VERSION 5.7 ;
BUSBITCHARS "[]" ;
DIVIDERCHAR "/" ;
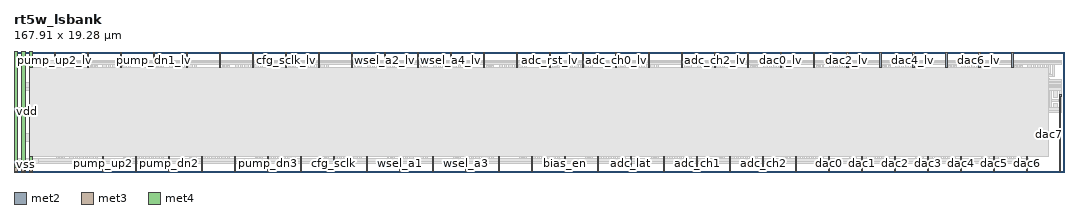
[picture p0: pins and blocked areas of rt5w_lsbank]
MACRO rt5w_lsbank
  CLASS BLOCK ;
  FOREIGN rt5w_lsbank ;
  ORIGIN 3.900 1.500 ;
  SIZE 167.910 BY 19.280 ;
  SYMMETRY X Y ;
  PIN adc_ch0
    DIRECTION INOUT ;
    USE SIGNAL ;
    PORT
      LAYER met2 ;
        RECT 99.945 -1.400 100.145 1.000 ;
    END
  END adc_ch0
  PIN adc_ch0_lv
    DIRECTION INOUT ;
    USE SIGNAL ;
    PORT
      LAYER met2 ;
        RECT 92.310 15.280 92.510 17.680 ;
    END
  END adc_ch0_lv
  PIN adc_ch1
    DIRECTION INOUT ;
    USE SIGNAL ;
    PORT
      LAYER met2 ;
        RECT 105.225 -1.400 105.425 1.000 ;
    END
  END adc_ch1
  PIN adc_ch1_lv
    DIRECTION INOUT ;
    USE SIGNAL ;
    PORT
      LAYER met2 ;
        RECT 97.590 15.280 97.790 17.680 ;
    END
  END adc_ch1_lv
  PIN adc_ch2
    DIRECTION INOUT ;
    USE SIGNAL ;
    PORT
      LAYER met2 ;
        RECT 115.785 -1.400 115.985 1.000 ;
    END
  END adc_ch2
  PIN adc_ch2_lv
    DIRECTION INOUT ;
    USE SIGNAL ;
    PORT
      LAYER met2 ;
        RECT 108.150 15.280 108.350 17.680 ;
    END
  END adc_ch2_lv
  PIN adc_ch3
    DIRECTION INOUT ;
    USE SIGNAL ;
    PORT
      LAYER met2 ;
        RECT 121.065 -1.400 121.265 1.000 ;
    END
  END adc_ch3
  PIN adc_ch3_lv
    DIRECTION INOUT ;
    USE SIGNAL ;
    PORT
      LAYER met2 ;
        RECT 113.430 15.280 113.630 17.680 ;
    END
  END adc_ch3_lv
  PIN adc_lat
    DIRECTION INOUT ;
    USE SIGNAL ;
    PORT
      LAYER met2 ;
        RECT 94.665 -1.400 94.865 1.000 ;
    END
  END adc_lat
  PIN adc_lat_lv
    DIRECTION INOUT ;
    USE SIGNAL ;
    PORT
      LAYER met2 ;
        RECT 87.030 15.280 87.230 17.680 ;
    END
  END adc_lat_lv
  PIN adc_rst
    DIRECTION INOUT ;
    USE SIGNAL ;
    PORT
      LAYER met2 ;
        RECT 89.385 -1.400 89.585 1.000 ;
    END
  END adc_rst
  PIN adc_rst_lv
    DIRECTION INOUT ;
    USE SIGNAL ;
    PORT
      LAYER met2 ;
        RECT 81.750 15.280 81.950 17.680 ;
    END
  END adc_rst_lv
  PIN bias_en
    DIRECTION INOUT ;
    USE SIGNAL ;
    PORT
      LAYER met2 ;
        RECT 84.105 -1.400 84.305 1.000 ;
    END
  END bias_en
  PIN bias_en_lv
    DIRECTION INOUT ;
    USE SIGNAL ;
    PORT
      LAYER met2 ;
        RECT 76.470 15.280 76.670 17.680 ;
    END
  END bias_en_lv
  PIN cfg_sclk
    DIRECTION INOUT ;
    USE SIGNAL ;
    PORT
      LAYER met2 ;
        RECT 47.145 -1.400 47.345 1.000 ;
    END
  END cfg_sclk
  PIN cfg_sclk_lv
    DIRECTION INOUT ;
    USE SIGNAL ;
    PORT
      LAYER met2 ;
        RECT 39.510 15.280 39.710 17.680 ;
    END
  END cfg_sclk_lv
  PIN cfg_sdat
    DIRECTION INOUT ;
    USE SIGNAL ;
    PORT
      LAYER met2 ;
        RECT 41.865 -1.400 42.065 1.000 ;
    END
  END cfg_sdat
  PIN cfg_sdat_lv
    DIRECTION INOUT ;
    USE SIGNAL ;
    PORT
      LAYER met2 ;
        RECT 34.230 15.280 34.430 17.680 ;
    END
  END cfg_sdat_lv
  PIN dac0
    DIRECTION INOUT ;
    USE SIGNAL ;
    PORT
      LAYER met2 ;
        RECT 126.345 -1.400 126.545 1.000 ;
    END
  END dac0
  PIN dac0_lv
    DIRECTION INOUT ;
    USE SIGNAL ;
    PORT
      LAYER met2 ;
        RECT 118.710 15.280 118.910 17.680 ;
    END
  END dac0_lv
  PIN dac1
    DIRECTION INOUT ;
    USE SIGNAL ;
    PORT
      LAYER met2 ;
        RECT 131.625 -1.400 131.825 1.000 ;
    END
  END dac1
  PIN dac1_lv
    DIRECTION INOUT ;
    USE SIGNAL ;
    PORT
      LAYER met2 ;
        RECT 123.990 15.280 124.190 17.680 ;
    END
  END dac1_lv
  PIN dac2
    DIRECTION INOUT ;
    USE SIGNAL ;
    PORT
      LAYER met2 ;
        RECT 136.905 -1.400 137.105 1.000 ;
    END
  END dac2
  PIN dac2_lv
    DIRECTION INOUT ;
    USE SIGNAL ;
    PORT
      LAYER met2 ;
        RECT 129.270 15.280 129.470 17.680 ;
    END
  END dac2_lv
  PIN dac3
    DIRECTION INOUT ;
    USE SIGNAL ;
    PORT
      LAYER met2 ;
        RECT 142.185 -1.400 142.385 1.000 ;
    END
  END dac3
  PIN dac3_lv
    DIRECTION INOUT ;
    USE SIGNAL ;
    PORT
      LAYER met2 ;
        RECT 134.550 15.280 134.750 17.680 ;
    END
  END dac3_lv
  PIN dac4
    DIRECTION INOUT ;
    USE SIGNAL ;
    PORT
      LAYER met2 ;
        RECT 147.465 -1.400 147.665 1.000 ;
    END
  END dac4
  PIN dac4_lv
    DIRECTION INOUT ;
    USE SIGNAL ;
    PORT
      LAYER met2 ;
        RECT 139.830 15.280 140.030 17.680 ;
    END
  END dac4_lv
  PIN dac5
    DIRECTION INOUT ;
    USE SIGNAL ;
    PORT
      LAYER met2 ;
        RECT 152.745 -1.400 152.945 1.000 ;
    END
  END dac5
  PIN dac5_lv
    DIRECTION INOUT ;
    USE SIGNAL ;
    PORT
      LAYER met2 ;
        RECT 145.110 15.280 145.310 17.680 ;
    END
  END dac5_lv
  PIN dac6
    DIRECTION INOUT ;
    USE SIGNAL ;
    PORT
      LAYER met2 ;
        RECT 158.025 -1.400 158.225 1.000 ;
    END
  END dac6
  PIN dac6_lv
    DIRECTION INOUT ;
    USE SIGNAL ;
    PORT
      LAYER met2 ;
        RECT 150.390 15.280 150.590 17.680 ;
    END
  END dac6_lv
  PIN dac7
    DIRECTION INOUT ;
    USE SIGNAL ;
    PORT
      LAYER met2 ;
        RECT 163.275 10.520 163.535 10.840 ;
        RECT 163.305 -1.400 163.505 10.520 ;
    END
  END dac7
  PIN dac7_lv
    DIRECTION INOUT ;
    USE SIGNAL ;
    PORT
      LAYER met2 ;
        RECT 155.670 15.280 155.870 17.680 ;
    END
  END dac7_lv
  PIN pump_dn1
    DIRECTION INOUT ;
    USE SIGNAL ;
    PORT
      LAYER met2 ;
        RECT 26.025 -1.400 26.225 1.000 ;
    END
  END pump_dn1
  PIN pump_dn1_lv
    DIRECTION INOUT ;
    USE SIGNAL ;
    PORT
      LAYER met2 ;
        RECT 18.390 15.280 18.590 17.680 ;
    END
  END pump_dn1_lv
  PIN pump_dn2
    DIRECTION INOUT ;
    USE SIGNAL ;
    PORT
      LAYER met2 ;
        RECT 20.745 -1.400 20.945 1.000 ;
    END
  END pump_dn2
  PIN pump_dn2_lv
    DIRECTION INOUT ;
    USE SIGNAL ;
    PORT
      LAYER met2 ;
        RECT 13.110 15.280 13.310 17.680 ;
    END
  END pump_dn2_lv
  PIN pump_dn3
    DIRECTION INOUT ;
    USE SIGNAL ;
    PORT
      LAYER met2 ;
        RECT 36.585 -1.400 36.785 1.000 ;
    END
  END pump_dn3
  PIN pump_dn3_lv
    DIRECTION INOUT ;
    USE SIGNAL ;
    PORT
      LAYER met2 ;
        RECT 28.950 15.280 29.150 17.680 ;
    END
  END pump_dn3_lv
  PIN pump_up1
    DIRECTION INOUT ;
    USE SIGNAL ;
    PORT
      LAYER met2 ;
        RECT 15.465 -1.400 15.665 1.000 ;
    END
  END pump_up1
  PIN pump_up1_lv
    DIRECTION INOUT ;
    USE SIGNAL ;
    PORT
      LAYER met2 ;
        RECT 7.830 15.280 8.030 17.680 ;
    END
  END pump_up1_lv
  PIN pump_up2
    DIRECTION INOUT ;
    USE SIGNAL ;
    PORT
      LAYER met2 ;
        RECT 10.185 -1.400 10.385 1.000 ;
    END
  END pump_up2
  PIN pump_up2_lv
    DIRECTION INOUT ;
    USE SIGNAL ;
    PORT
      LAYER met2 ;
        RECT 2.550 15.280 2.750 17.680 ;
    END
  END pump_up2_lv
  PIN pump_up3
    DIRECTION INOUT ;
    USE SIGNAL ;
    PORT
      LAYER met2 ;
        RECT 31.305 -1.400 31.505 1.000 ;
    END
  END pump_up3
  PIN pump_up3_lv
    DIRECTION INOUT ;
    USE SIGNAL ;
    PORT
      LAYER met2 ;
        RECT 23.670 15.280 23.870 17.680 ;
    END
  END pump_up3_lv
  PIN vb_probe_en
    DIRECTION INOUT ;
    USE SIGNAL ;
    PORT
      LAYER met2 ;
        RECT 110.505 -1.400 110.705 1.000 ;
    END
  END vb_probe_en
  PIN vb_probe_en_lv
    DIRECTION INOUT ;
    USE SIGNAL ;
    PORT
      LAYER met2 ;
        RECT 102.870 15.280 103.070 17.680 ;
    END
  END vb_probe_en_lv
  PIN vdd
    DIRECTION INOUT ;
    USE SIGNAL ;
    PORT
      LAYER met3 ;
        RECT -2.650 -1.350 -2.150 -0.850 ;
      LAYER met4 ;
        RECT -2.700 -1.500 -2.100 17.780 ;
    END
  END vdd
  PIN vddl
    DIRECTION INOUT ;
    USE SIGNAL ;
    PORT
      LAYER met3 ;
        RECT -1.450 -1.350 -0.950 -0.850 ;
      LAYER met4 ;
        RECT -1.500 -1.500 -0.900 1.000 ;
        RECT -1.500 1.000 -1.400 15.280 ;
        RECT -1.500 15.280 -0.900 17.780 ;
    END
  END vddl
  PIN vss
    DIRECTION INOUT ;
    USE SIGNAL ;
    PORT
      LAYER met3 ;
        RECT -3.850 -1.350 -3.350 -0.850 ;
      LAYER met4 ;
        RECT -3.900 -1.500 -3.300 17.780 ;
    END
  END vss
  PIN wsel_a0
    DIRECTION INOUT ;
    USE SIGNAL ;
    PORT
      LAYER met2 ;
        RECT 52.425 -1.400 52.625 1.000 ;
    END
  END wsel_a0
  PIN wsel_a0_lv
    DIRECTION INOUT ;
    USE SIGNAL ;
    PORT
      LAYER met2 ;
        RECT 44.790 15.280 44.990 17.680 ;
    END
  END wsel_a0_lv
  PIN wsel_a1
    DIRECTION INOUT ;
    USE SIGNAL ;
    PORT
      LAYER met2 ;
        RECT 57.705 -1.400 57.905 1.000 ;
    END
  END wsel_a1
  PIN wsel_a1_lv
    DIRECTION INOUT ;
    USE SIGNAL ;
    PORT
      LAYER met2 ;
        RECT 50.070 15.280 50.270 17.680 ;
    END
  END wsel_a1_lv
  PIN wsel_a2
    DIRECTION INOUT ;
    USE SIGNAL ;
    PORT
      LAYER met2 ;
        RECT 62.985 -1.400 63.185 1.000 ;
    END
  END wsel_a2
  PIN wsel_a2_lv
    DIRECTION INOUT ;
    USE SIGNAL ;
    PORT
      LAYER met2 ;
        RECT 55.350 15.280 55.550 17.680 ;
    END
  END wsel_a2_lv
  PIN wsel_a3
    DIRECTION INOUT ;
    USE SIGNAL ;
    PORT
      LAYER met2 ;
        RECT 68.265 -1.400 68.465 1.000 ;
    END
  END wsel_a3
  PIN wsel_a3_lv
    DIRECTION INOUT ;
    USE SIGNAL ;
    PORT
      LAYER met2 ;
        RECT 60.630 15.280 60.830 17.680 ;
    END
  END wsel_a3_lv
  PIN wsel_a4
    DIRECTION INOUT ;
    USE SIGNAL ;
    PORT
      LAYER met2 ;
        RECT 73.545 -1.400 73.745 1.000 ;
    END
  END wsel_a4
  PIN wsel_a4_lv
    DIRECTION INOUT ;
    USE SIGNAL ;
    PORT
      LAYER met2 ;
        RECT 65.910 15.280 66.110 17.680 ;
    END
  END wsel_a4_lv
  PIN wsel_e
    DIRECTION INOUT ;
    USE SIGNAL ;
    PORT
      LAYER met2 ;
        RECT 78.825 -1.400 79.025 1.000 ;
    END
  END wsel_e
  PIN wsel_e_lv
    DIRECTION INOUT ;
    USE SIGNAL ;
    PORT
      LAYER met2 ;
        RECT 71.190 15.280 71.390 17.680 ;
    END
  END wsel_e_lv
  OBS
    LAYER li1 ;
      RECT 0.000 -0.085 158.400 0.085 ;
      RECT 78.970 0.255 82.090 0.425 ;
      RECT -1.400 1.000 161.510 13.805 ;
      RECT -1.400 13.805 162.200 14.135 ;
      RECT -1.400 14.135 161.290 15.280 ;
      RECT 5.280 16.195 163.680 16.365 ;
      RECT 122.120 0.595 122.450 1.000 ;
      RECT 121.210 0.255 124.330 0.425 ;
      RECT 162.330 8.535 162.920 9.445 ;
      RECT 163.330 9.555 163.570 10.225 ;
      RECT 122.770 0.425 123.360 1.000 ;
      RECT 123.680 0.595 124.010 1.000 ;
      RECT 124.330 0.255 124.920 1.000 ;
      RECT 163.240 8.655 163.570 9.555 ;
      RECT 125.240 0.515 125.570 1.000 ;
      RECT 129.695 0.735 129.985 1.000 ;
      RECT 130.155 0.565 130.425 1.000 ;
      RECT 129.815 0.335 130.765 0.565 ;
      RECT 130.595 0.735 130.905 1.000 ;
      RECT 131.770 0.425 132.360 1.000 ;
      RECT 132.680 0.595 133.010 1.000 ;
      RECT 133.330 0.425 133.920 1.000 ;
      RECT 134.240 0.595 134.570 1.000 ;
      RECT 134.890 0.255 135.480 1.000 ;
      RECT 131.770 0.255 134.890 0.425 ;
      RECT 135.800 0.515 136.130 1.000 ;
      RECT 140.255 0.735 140.545 1.000 ;
      RECT 140.715 0.565 140.985 1.000 ;
      RECT 140.375 0.335 141.325 0.565 ;
      RECT 141.155 0.735 141.465 1.000 ;
      RECT 142.330 0.425 142.920 1.000 ;
      RECT 143.240 0.595 143.570 1.000 ;
      RECT 143.890 0.425 144.480 1.000 ;
      RECT 144.800 0.595 145.130 1.000 ;
      RECT 145.450 0.255 146.040 1.000 ;
      RECT 142.330 0.255 145.450 0.425 ;
      RECT 146.360 0.515 146.690 1.000 ;
      RECT 150.815 0.735 151.105 1.000 ;
      RECT 151.275 0.565 151.545 1.000 ;
      RECT 150.935 0.335 151.885 0.565 ;
      RECT 151.715 0.735 152.025 1.000 ;
      RECT 152.890 0.425 153.480 1.000 ;
      RECT 153.800 0.595 154.130 1.000 ;
      RECT 154.450 0.425 155.040 1.000 ;
      RECT 155.360 0.595 155.690 1.000 ;
      RECT 156.010 0.255 156.600 1.000 ;
      RECT 152.890 0.255 156.010 0.425 ;
      RECT 124.415 15.280 124.705 15.545 ;
      RECT 125.315 15.280 125.625 15.545 ;
      RECT 134.975 15.280 135.265 15.545 ;
      RECT 135.875 15.280 136.185 15.545 ;
      RECT 145.535 15.280 145.825 15.545 ;
      RECT 146.435 15.280 146.745 15.545 ;
      RECT 156.095 15.280 156.385 15.545 ;
      RECT 156.995 15.280 157.305 15.545 ;
      RECT 127.400 15.280 127.730 15.685 ;
      RECT 128.960 15.280 129.290 15.685 ;
      RECT 137.960 15.280 138.290 15.685 ;
      RECT 139.520 15.280 139.850 15.685 ;
      RECT 148.520 15.280 148.850 15.685 ;
      RECT 150.080 15.280 150.410 15.685 ;
      RECT 159.080 15.280 159.410 15.685 ;
      RECT 160.640 15.280 160.970 15.685 ;
      RECT 130.520 15.280 130.850 15.765 ;
      RECT 141.080 15.280 141.410 15.765 ;
      RECT 151.640 15.280 151.970 15.765 ;
      RECT 161.510 8.055 163.680 8.225 ;
      RECT 161.965 9.725 163.160 10.055 ;
      RECT 156.920 0.515 157.250 1.000 ;
      RECT 162.200 13.805 162.530 15.765 ;
      RECT 161.635 8.655 161.965 11.875 ;
      RECT 161.510 12.575 161.715 13.485 ;
      RECT 161.510 12.125 163.680 12.295 ;
      RECT 126.490 15.280 127.080 15.855 ;
      RECT 128.050 15.280 128.640 15.855 ;
      RECT 137.050 15.280 137.640 15.855 ;
      RECT 138.610 15.280 139.200 15.855 ;
      RECT 147.610 15.280 148.200 15.855 ;
      RECT 149.170 15.280 149.760 15.855 ;
      RECT 158.170 15.280 158.760 15.855 ;
      RECT 159.730 15.280 160.320 15.855 ;
      RECT 124.535 15.715 125.485 15.945 ;
      RECT 124.875 15.280 125.145 15.715 ;
      RECT 135.095 15.715 136.045 15.945 ;
      RECT 135.435 15.280 135.705 15.715 ;
      RECT 145.655 15.715 146.605 15.945 ;
      RECT 145.995 15.280 146.265 15.715 ;
      RECT 156.215 15.715 157.165 15.945 ;
      RECT 156.555 15.280 156.825 15.715 ;
      RECT 126.490 15.855 129.610 16.025 ;
      RECT 129.610 15.280 130.200 16.025 ;
      RECT 137.050 15.855 140.170 16.025 ;
      RECT 140.170 15.280 140.760 16.025 ;
      RECT 147.610 15.855 150.730 16.025 ;
      RECT 150.730 15.280 151.320 16.025 ;
      RECT 158.170 15.855 161.880 16.025 ;
      RECT 161.290 14.135 161.510 15.855 ;
      RECT 161.510 14.305 161.880 15.855 ;
      RECT 162.330 10.335 162.920 11.875 ;
      RECT 163.240 10.225 163.570 11.875 ;
      RECT 81.440 0.595 81.770 1.000 ;
      RECT 83.000 0.515 83.330 1.000 ;
      RECT 87.455 0.735 87.745 1.000 ;
      RECT 87.915 0.565 88.185 1.000 ;
      RECT 85.160 15.280 85.490 15.685 ;
      RECT 86.720 15.280 87.050 15.685 ;
      RECT 95.720 15.280 96.050 15.685 ;
      RECT 97.280 15.280 97.610 15.685 ;
      RECT 106.280 15.280 106.610 15.685 ;
      RECT 107.840 15.280 108.170 15.685 ;
      RECT 116.840 15.280 117.170 15.685 ;
      RECT 118.400 15.280 118.730 15.685 ;
      RECT 87.575 0.335 88.525 0.565 ;
      RECT 88.355 0.735 88.665 1.000 ;
      RECT 89.530 0.425 90.120 1.000 ;
      RECT 90.440 0.595 90.770 1.000 ;
      RECT 91.090 0.425 91.680 1.000 ;
      RECT 92.000 0.595 92.330 1.000 ;
      RECT 92.650 0.255 93.240 1.000 ;
      RECT 89.530 0.255 92.650 0.425 ;
      RECT 88.280 15.280 88.610 15.765 ;
      RECT 98.840 15.280 99.170 15.765 ;
      RECT 109.400 15.280 109.730 15.765 ;
      RECT 119.960 15.280 120.290 15.765 ;
      RECT 93.560 0.515 93.890 1.000 ;
      RECT 98.015 0.735 98.305 1.000 ;
      RECT 98.475 0.565 98.745 1.000 ;
      RECT 98.135 0.335 99.085 0.565 ;
      RECT 98.915 0.735 99.225 1.000 ;
      RECT 100.090 0.425 100.680 1.000 ;
      RECT 101.000 0.595 101.330 1.000 ;
      RECT 101.650 0.425 102.240 1.000 ;
      RECT 102.560 0.595 102.890 1.000 ;
      RECT 103.210 0.255 103.800 1.000 ;
      RECT 84.250 15.280 84.840 15.855 ;
      RECT 85.810 15.280 86.400 15.855 ;
      RECT 94.810 15.280 95.400 15.855 ;
      RECT 96.370 15.280 96.960 15.855 ;
      RECT 105.370 15.280 105.960 15.855 ;
      RECT 106.930 15.280 107.520 15.855 ;
      RECT 115.930 15.280 116.520 15.855 ;
      RECT 117.490 15.280 118.080 15.855 ;
      RECT 100.090 0.255 103.210 0.425 ;
      RECT 104.120 0.515 104.450 1.000 ;
      RECT 108.575 0.735 108.865 1.000 ;
      RECT 109.035 0.565 109.305 1.000 ;
      RECT 108.695 0.335 109.645 0.565 ;
      RECT 109.475 0.735 109.785 1.000 ;
      RECT 110.650 0.425 111.240 1.000 ;
      RECT 111.560 0.595 111.890 1.000 ;
      RECT 82.295 15.715 83.245 15.945 ;
      RECT 82.635 15.280 82.905 15.715 ;
      RECT 92.855 15.715 93.805 15.945 ;
      RECT 93.195 15.280 93.465 15.715 ;
      RECT 103.415 15.715 104.365 15.945 ;
      RECT 103.755 15.280 104.025 15.715 ;
      RECT 113.975 15.715 114.925 15.945 ;
      RECT 114.315 15.280 114.585 15.715 ;
      RECT 112.210 0.425 112.800 1.000 ;
      RECT 113.120 0.595 113.450 1.000 ;
      RECT 113.770 0.255 114.360 1.000 ;
      RECT 110.650 0.255 113.770 0.425 ;
      RECT 114.680 0.515 115.010 1.000 ;
      RECT 119.135 0.735 119.425 1.000 ;
      RECT 119.595 0.565 119.865 1.000 ;
      RECT 82.175 15.280 82.465 15.545 ;
      RECT 84.250 15.855 87.370 16.025 ;
      RECT 87.370 15.280 87.960 16.025 ;
      RECT 94.810 15.855 97.930 16.025 ;
      RECT 97.930 15.280 98.520 16.025 ;
      RECT 105.370 15.855 108.490 16.025 ;
      RECT 108.490 15.280 109.080 16.025 ;
      RECT 115.930 15.855 119.050 16.025 ;
      RECT 119.050 15.280 119.640 16.025 ;
      RECT 83.075 15.280 83.385 15.545 ;
      RECT 92.735 15.280 93.025 15.545 ;
      RECT 93.635 15.280 93.945 15.545 ;
      RECT 103.295 15.280 103.585 15.545 ;
      RECT 104.195 15.280 104.505 15.545 ;
      RECT 113.855 15.280 114.145 15.545 ;
      RECT 114.755 15.280 115.065 15.545 ;
      RECT 119.255 0.335 120.205 0.565 ;
      RECT 120.035 0.735 120.345 1.000 ;
      RECT 121.210 0.425 121.800 1.000 ;
      RECT 82.090 0.255 82.680 1.000 ;
      RECT 39.850 0.255 40.440 1.000 ;
      RECT 77.795 0.735 78.105 1.000 ;
      RECT 78.970 0.425 79.560 1.000 ;
      RECT 79.880 0.595 80.210 1.000 ;
      RECT 80.530 0.425 81.120 1.000 ;
      RECT 42.920 15.280 43.250 15.685 ;
      RECT 44.480 15.280 44.810 15.685 ;
      RECT 53.480 15.280 53.810 15.685 ;
      RECT 55.040 15.280 55.370 15.685 ;
      RECT 64.040 15.280 64.370 15.685 ;
      RECT 65.600 15.280 65.930 15.685 ;
      RECT 74.600 15.280 74.930 15.685 ;
      RECT 76.160 15.280 76.490 15.685 ;
      RECT 46.040 15.280 46.370 15.765 ;
      RECT 56.600 15.280 56.930 15.765 ;
      RECT 67.160 15.280 67.490 15.765 ;
      RECT 77.720 15.280 78.050 15.765 ;
      RECT 72.515 15.280 72.825 15.545 ;
      RECT 42.010 15.280 42.600 15.855 ;
      RECT 43.570 15.280 44.160 15.855 ;
      RECT 52.570 15.280 53.160 15.855 ;
      RECT 54.130 15.280 54.720 15.855 ;
      RECT 63.130 15.280 63.720 15.855 ;
      RECT 64.690 15.280 65.280 15.855 ;
      RECT 73.690 15.280 74.280 15.855 ;
      RECT 75.250 15.280 75.840 15.855 ;
      RECT 40.760 0.515 41.090 1.000 ;
      RECT 45.215 0.735 45.505 1.000 ;
      RECT 45.675 0.565 45.945 1.000 ;
      RECT 45.335 0.335 46.285 0.565 ;
      RECT 46.115 0.735 46.425 1.000 ;
      RECT 47.290 0.425 47.880 1.000 ;
      RECT 48.200 0.595 48.530 1.000 ;
      RECT 48.850 0.425 49.440 1.000 ;
      RECT 49.760 0.595 50.090 1.000 ;
      RECT 50.410 0.255 51.000 1.000 ;
      RECT 47.290 0.255 50.410 0.425 ;
      RECT 51.320 0.515 51.650 1.000 ;
      RECT 55.775 0.735 56.065 1.000 ;
      RECT 56.235 0.565 56.505 1.000 ;
      RECT 55.895 0.335 56.845 0.565 ;
      RECT 40.055 15.715 41.005 15.945 ;
      RECT 40.395 15.280 40.665 15.715 ;
      RECT 50.615 15.715 51.565 15.945 ;
      RECT 50.955 15.280 51.225 15.715 ;
      RECT 61.175 15.715 62.125 15.945 ;
      RECT 61.515 15.280 61.785 15.715 ;
      RECT 71.735 15.715 72.685 15.945 ;
      RECT 72.075 15.280 72.345 15.715 ;
      RECT 56.675 0.735 56.985 1.000 ;
      RECT 57.850 0.425 58.440 1.000 ;
      RECT 58.760 0.595 59.090 1.000 ;
      RECT 59.410 0.425 60.000 1.000 ;
      RECT 60.320 0.595 60.650 1.000 ;
      RECT 60.970 0.255 61.560 1.000 ;
      RECT 57.850 0.255 60.970 0.425 ;
      RECT 61.880 0.515 62.210 1.000 ;
      RECT 66.335 0.735 66.625 1.000 ;
      RECT 66.795 0.565 67.065 1.000 ;
      RECT 66.455 0.335 67.405 0.565 ;
      RECT 67.235 0.735 67.545 1.000 ;
      RECT 68.410 0.425 69.000 1.000 ;
      RECT 69.320 0.595 69.650 1.000 ;
      RECT 69.970 0.425 70.560 1.000 ;
      RECT 70.880 0.595 71.210 1.000 ;
      RECT 42.010 15.855 45.130 16.025 ;
      RECT 45.130 15.280 45.720 16.025 ;
      RECT 52.570 15.855 55.690 16.025 ;
      RECT 55.690 15.280 56.280 16.025 ;
      RECT 63.130 15.855 66.250 16.025 ;
      RECT 66.250 15.280 66.840 16.025 ;
      RECT 73.690 15.855 76.810 16.025 ;
      RECT 76.810 15.280 77.400 16.025 ;
      RECT 71.530 0.255 72.120 1.000 ;
      RECT 68.410 0.255 71.530 0.425 ;
      RECT 72.440 0.515 72.770 1.000 ;
      RECT 76.895 0.735 77.185 1.000 ;
      RECT 77.355 0.565 77.625 1.000 ;
      RECT 77.015 0.335 77.965 0.565 ;
      RECT 39.935 15.280 40.225 15.545 ;
      RECT 40.835 15.280 41.145 15.545 ;
      RECT 50.495 15.280 50.785 15.545 ;
      RECT 51.395 15.280 51.705 15.545 ;
      RECT 61.055 15.280 61.345 15.545 ;
      RECT 61.955 15.280 62.265 15.545 ;
      RECT 71.615 15.280 71.905 15.545 ;
      RECT 6.610 0.425 7.200 1.000 ;
      RECT 7.520 0.595 7.850 1.000 ;
      RECT 13.995 0.565 14.265 1.000 ;
      RECT 13.655 0.335 14.605 0.565 ;
      RECT 14.435 0.735 14.745 1.000 ;
      RECT 15.610 0.425 16.200 1.000 ;
      RECT 16.520 0.595 16.850 1.000 ;
      RECT 17.170 0.425 17.760 1.000 ;
      RECT 18.080 0.595 18.410 1.000 ;
      RECT 18.730 0.255 19.320 1.000 ;
      RECT 15.610 0.255 18.730 0.425 ;
      RECT 19.640 0.515 19.970 1.000 ;
      RECT 8.375 15.715 9.325 15.945 ;
      RECT 8.715 15.280 8.985 15.715 ;
      RECT 18.935 15.715 19.885 15.945 ;
      RECT 19.275 15.280 19.545 15.715 ;
      RECT 29.495 15.715 30.445 15.945 ;
      RECT 29.835 15.280 30.105 15.715 ;
      RECT 24.095 0.735 24.385 1.000 ;
      RECT 24.555 0.565 24.825 1.000 ;
      RECT 24.215 0.335 25.165 0.565 ;
      RECT 24.995 0.735 25.305 1.000 ;
      RECT 26.170 0.425 26.760 1.000 ;
      RECT 27.080 0.595 27.410 1.000 ;
      RECT 14.360 15.280 14.690 15.765 ;
      RECT 24.920 15.280 25.250 15.765 ;
      RECT 35.480 15.280 35.810 15.765 ;
      RECT 8.170 0.255 8.760 1.000 ;
      RECT 5.050 0.255 8.170 0.425 ;
      RECT 9.080 0.515 9.410 1.000 ;
      RECT 13.535 0.735 13.825 1.000 ;
      RECT 27.730 0.425 28.320 1.000 ;
      RECT 28.640 0.595 28.970 1.000 ;
      RECT 29.290 0.255 29.880 1.000 ;
      RECT 26.170 0.255 29.290 0.425 ;
      RECT 30.200 0.515 30.530 1.000 ;
      RECT 34.655 0.735 34.945 1.000 ;
      RECT 35.115 0.565 35.385 1.000 ;
      RECT 34.775 0.335 35.725 0.565 ;
      RECT 35.555 0.735 35.865 1.000 ;
      RECT 36.730 0.425 37.320 1.000 ;
      RECT 37.640 0.595 37.970 1.000 ;
      RECT 10.330 15.855 13.450 16.025 ;
      RECT 13.450 15.280 14.040 16.025 ;
      RECT 20.890 15.855 24.010 16.025 ;
      RECT 24.010 15.280 24.600 16.025 ;
      RECT 31.450 15.855 34.570 16.025 ;
      RECT 34.570 15.280 35.160 16.025 ;
      RECT 38.290 0.425 38.880 1.000 ;
      RECT 39.200 0.595 39.530 1.000 ;
      RECT 11.240 15.280 11.570 15.685 ;
      RECT 10.330 15.280 10.920 15.855 ;
      RECT 11.890 15.280 12.480 15.855 ;
      RECT 20.890 15.280 21.480 15.855 ;
      RECT 22.450 15.280 23.040 15.855 ;
      RECT 31.450 15.280 32.040 15.855 ;
      RECT 33.010 15.280 33.600 15.855 ;
      RECT 12.800 15.280 13.130 15.685 ;
      RECT 21.800 15.280 22.130 15.685 ;
      RECT 23.360 15.280 23.690 15.685 ;
      RECT 32.360 15.280 32.690 15.685 ;
      RECT 33.920 15.280 34.250 15.685 ;
      RECT 8.255 15.280 8.545 15.545 ;
      RECT 9.155 15.280 9.465 15.545 ;
      RECT 18.815 15.280 19.105 15.545 ;
      RECT 19.715 15.280 20.025 15.545 ;
      RECT 29.375 15.280 29.665 15.545 ;
      RECT 30.275 15.280 30.585 15.545 ;
      RECT 2.975 0.735 3.265 1.000 ;
      RECT 3.435 0.565 3.705 1.000 ;
      RECT 3.095 0.335 4.045 0.565 ;
      RECT 36.730 0.255 39.850 0.425 ;
      RECT 3.875 0.735 4.185 1.000 ;
      RECT 5.050 0.425 5.640 1.000 ;
      RECT 5.960 0.595 6.290 1.000 ;
    LAYER met1 ;
      RECT 0.000 -0.115 158.400 0.115 ;
      RECT -3.900 -0.115 0.000 0.625 ;
      RECT 0.000 0.255 158.400 0.625 ;
      RECT 163.260 10.505 163.550 10.855 ;
      RECT 161.510 8.025 163.680 8.255 ;
      RECT -3.900 7.515 -1.400 8.765 ;
      RECT -1.400 13.260 161.510 15.280 ;
      RECT 161.510 12.095 163.680 12.325 ;
      RECT -1.500 12.975 163.610 13.260 ;
      RECT -1.400 12.835 161.510 12.975 ;
      RECT -2.700 11.585 163.680 11.955 ;
      RECT -2.700 11.955 161.510 12.835 ;
      RECT 161.510 12.465 163.680 12.835 ;
      RECT -1.400 1.000 161.510 11.585 ;
      RECT -1.500 3.020 -1.400 3.305 ;
      RECT -2.700 3.445 -1.400 4.695 ;
      RECT 161.510 8.395 163.680 8.765 ;
      RECT 5.280 15.655 163.680 16.025 ;
      RECT -3.900 15.655 5.280 16.395 ;
      RECT 5.280 16.165 163.680 16.395 ;
    LAYER met2 ;
      RECT -3.900 -0.400 -3.300 16.680 ;
      RECT -2.700 -0.400 -2.100 16.680 ;
      RECT -0.900 1.000 161.510 15.280 ;
      RECT -1.500 -0.400 -0.900 16.680 ;
    LAYER met3 ;
      RECT -3.850 5.890 -3.350 6.390 ;
      RECT -2.650 5.890 -2.150 6.390 ;
      RECT -3.850 9.890 -3.350 10.390 ;
      RECT -2.650 9.890 -2.150 10.390 ;
      RECT -1.450 9.890 -1.400 10.390 ;
      RECT -1.400 1.000 161.510 15.280 ;
      RECT -1.450 5.890 -1.400 6.390 ;
    LAYER met4 ;
      RECT -1.400 1.000 161.510 15.280 ;
  END
END rt5w_lsbank
END LIBRARY
